VERSION 5.7 ;
BUSBITCHARS "[]" ;
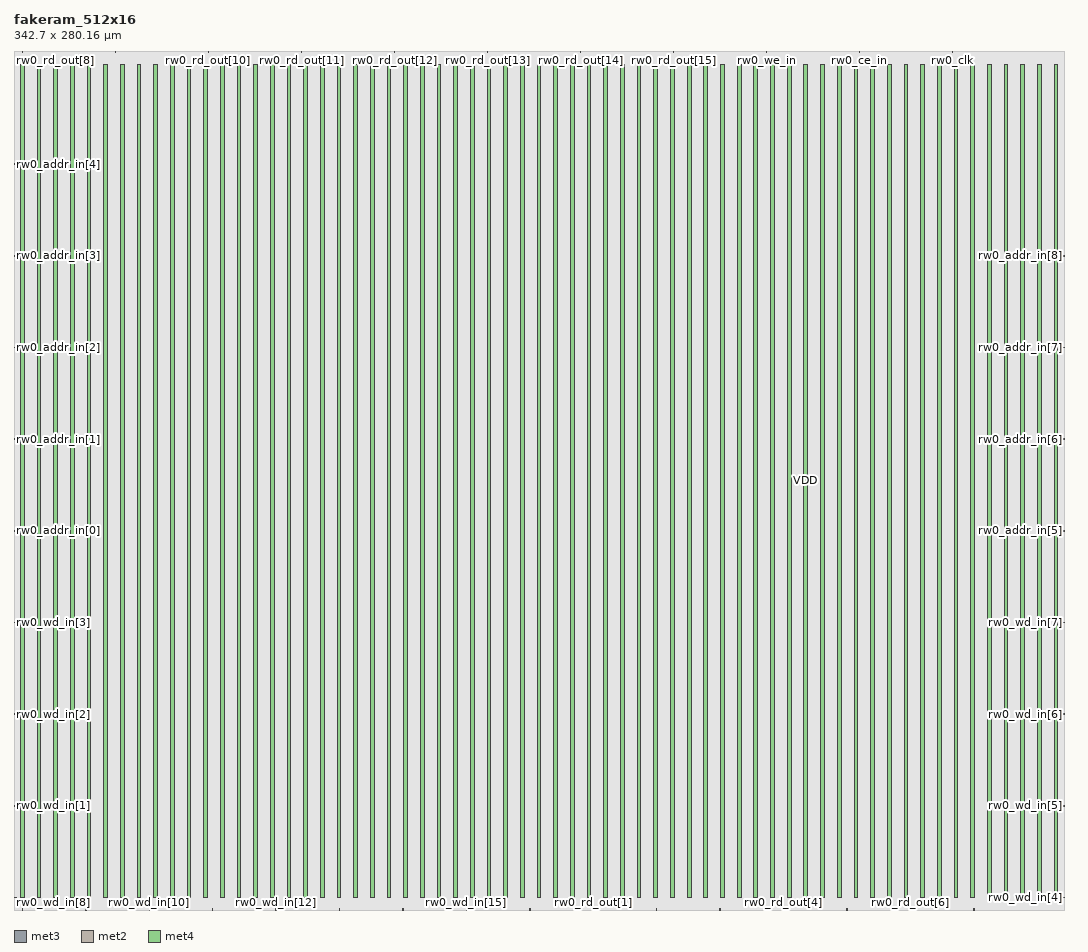
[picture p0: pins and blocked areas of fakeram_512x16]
MACRO fakeram_512x16
  FOREIGN fakeram_512x16 0 0 ;
  SYMMETRY X Y R90 ;
  SIZE 342.700 BY 280.160 ;
  CLASS BLOCK ;
  PIN rw0_wd_in[0]
    DIRECTION INPUT ;
    USE SIGNAL ;
    SHAPE ABUTMENT ;
    PORT
      LAYER met3 ;
      RECT 0.000 3.930 0.900 4.230 ;
    END
  END rw0_wd_in[0]
  PIN rw0_wd_in[1]
    DIRECTION INPUT ;
    USE SIGNAL ;
    SHAPE ABUTMENT ;
    PORT
      LAYER met3 ;
      RECT 0.000 33.850 0.900 34.150 ;
    END
  END rw0_wd_in[1]
  PIN rw0_wd_in[2]
    DIRECTION INPUT ;
    USE SIGNAL ;
    SHAPE ABUTMENT ;
    PORT
      LAYER met3 ;
      RECT 0.000 63.770 0.900 64.070 ;
    END
  END rw0_wd_in[2]
  PIN rw0_wd_in[3]
    DIRECTION INPUT ;
    USE SIGNAL ;
    SHAPE ABUTMENT ;
    PORT
      LAYER met3 ;
      RECT 0.000 93.690 0.900 93.990 ;
    END
  END rw0_wd_in[3]
  PIN rw0_wd_in[4]
    DIRECTION INPUT ;
    USE SIGNAL ;
    SHAPE ABUTMENT ;
    PORT
      LAYER met3 ;
      RECT 341.800 3.930 342.700 4.230 ;
    END
  END rw0_wd_in[4]
  PIN rw0_wd_in[5]
    DIRECTION INPUT ;
    USE SIGNAL ;
    SHAPE ABUTMENT ;
    PORT
      LAYER met3 ;
      RECT 341.800 33.850 342.700 34.150 ;
    END
  END rw0_wd_in[5]
  PIN rw0_wd_in[6]
    DIRECTION INPUT ;
    USE SIGNAL ;
    SHAPE ABUTMENT ;
    PORT
      LAYER met3 ;
      RECT 341.800 63.770 342.700 64.070 ;
    END
  END rw0_wd_in[6]
  PIN rw0_wd_in[7]
    DIRECTION INPUT ;
    USE SIGNAL ;
    SHAPE ABUTMENT ;
    PORT
      LAYER met3 ;
      RECT 341.800 93.690 342.700 93.990 ;
    END
  END rw0_wd_in[7]
  PIN rw0_wd_in[8]
    DIRECTION INPUT ;
    USE SIGNAL ;
    SHAPE ABUTMENT ;
    PORT
      LAYER met2 ;
      RECT 2.690 0.000 2.830 0.420 ;
    END
  END rw0_wd_in[8]
  PIN rw0_wd_in[9]
    DIRECTION INPUT ;
    USE SIGNAL ;
    SHAPE ABUTMENT ;
    PORT
      LAYER met2 ;
      RECT 23.390 0.000 23.530 0.420 ;
    END
  END rw0_wd_in[9]
  PIN rw0_wd_in[10]
    DIRECTION INPUT ;
    USE SIGNAL ;
    SHAPE ABUTMENT ;
    PORT
      LAYER met2 ;
      RECT 44.090 0.000 44.230 0.420 ;
    END
  END rw0_wd_in[10]
  PIN rw0_wd_in[11]
    DIRECTION INPUT ;
    USE SIGNAL ;
    SHAPE ABUTMENT ;
    PORT
      LAYER met2 ;
      RECT 64.790 0.000 64.930 0.420 ;
    END
  END rw0_wd_in[11]
  PIN rw0_wd_in[12]
    DIRECTION INPUT ;
    USE SIGNAL ;
    SHAPE ABUTMENT ;
    PORT
      LAYER met2 ;
      RECT 85.490 0.000 85.630 0.420 ;
    END
  END rw0_wd_in[12]
  PIN rw0_wd_in[13]
    DIRECTION INPUT ;
    USE SIGNAL ;
    SHAPE ABUTMENT ;
    PORT
      LAYER met2 ;
      RECT 106.190 0.000 106.330 0.420 ;
    END
  END rw0_wd_in[13]
  PIN rw0_wd_in[14]
    DIRECTION INPUT ;
    USE SIGNAL ;
    SHAPE ABUTMENT ;
    PORT
      LAYER met2 ;
      RECT 126.890 0.000 127.030 0.420 ;
    END
  END rw0_wd_in[14]
  PIN rw0_wd_in[15]
    DIRECTION INPUT ;
    USE SIGNAL ;
    SHAPE ABUTMENT ;
    PORT
      LAYER met2 ;
      RECT 147.590 0.000 147.730 0.420 ;
    END
  END rw0_wd_in[15]
  PIN rw0_rd_out[0]
    DIRECTION OUTPUT ;
    USE SIGNAL ;
    SHAPE ABUTMENT ;
    PORT
      LAYER met2 ;
      RECT 168.290 0.000 168.430 0.420 ;
    END
  END rw0_rd_out[0]
  PIN rw0_rd_out[1]
    DIRECTION OUTPUT ;
    USE SIGNAL ;
    SHAPE ABUTMENT ;
    PORT
      LAYER met2 ;
      RECT 188.990 0.000 189.130 0.420 ;
    END
  END rw0_rd_out[1]
  PIN rw0_rd_out[2]
    DIRECTION OUTPUT ;
    USE SIGNAL ;
    SHAPE ABUTMENT ;
    PORT
      LAYER met2 ;
      RECT 209.690 0.000 209.830 0.420 ;
    END
  END rw0_rd_out[2]
  PIN rw0_rd_out[3]
    DIRECTION OUTPUT ;
    USE SIGNAL ;
    SHAPE ABUTMENT ;
    PORT
      LAYER met2 ;
      RECT 230.390 0.000 230.530 0.420 ;
    END
  END rw0_rd_out[3]
  PIN rw0_rd_out[4]
    DIRECTION OUTPUT ;
    USE SIGNAL ;
    SHAPE ABUTMENT ;
    PORT
      LAYER met2 ;
      RECT 251.090 0.000 251.230 0.420 ;
    END
  END rw0_rd_out[4]
  PIN rw0_rd_out[5]
    DIRECTION OUTPUT ;
    USE SIGNAL ;
    SHAPE ABUTMENT ;
    PORT
      LAYER met2 ;
      RECT 271.790 0.000 271.930 0.420 ;
    END
  END rw0_rd_out[5]
  PIN rw0_rd_out[6]
    DIRECTION OUTPUT ;
    USE SIGNAL ;
    SHAPE ABUTMENT ;
    PORT
      LAYER met2 ;
      RECT 292.490 0.000 292.630 0.420 ;
    END
  END rw0_rd_out[6]
  PIN rw0_rd_out[7]
    DIRECTION OUTPUT ;
    USE SIGNAL ;
    SHAPE ABUTMENT ;
    PORT
      LAYER met2 ;
      RECT 313.190 0.000 313.330 0.420 ;
    END
  END rw0_rd_out[7]
  PIN rw0_rd_out[8]
    DIRECTION OUTPUT ;
    USE SIGNAL ;
    SHAPE ABUTMENT ;
    PORT
      LAYER met2 ;
      RECT 2.690 279.740 2.830 280.160 ;
    END
  END rw0_rd_out[8]
  PIN rw0_rd_out[9]
    DIRECTION OUTPUT ;
    USE SIGNAL ;
    SHAPE ABUTMENT ;
    PORT
      LAYER met2 ;
      RECT 33.050 279.740 33.190 280.160 ;
    END
  END rw0_rd_out[9]
  PIN rw0_rd_out[10]
    DIRECTION OUTPUT ;
    USE SIGNAL ;
    SHAPE ABUTMENT ;
    PORT
      LAYER met2 ;
      RECT 63.410 279.740 63.550 280.160 ;
    END
  END rw0_rd_out[10]
  PIN rw0_rd_out[11]
    DIRECTION OUTPUT ;
    USE SIGNAL ;
    SHAPE ABUTMENT ;
    PORT
      LAYER met2 ;
      RECT 93.770 279.740 93.910 280.160 ;
    END
  END rw0_rd_out[11]
  PIN rw0_rd_out[12]
    DIRECTION OUTPUT ;
    USE SIGNAL ;
    SHAPE ABUTMENT ;
    PORT
      LAYER met2 ;
      RECT 124.130 279.740 124.270 280.160 ;
    END
  END rw0_rd_out[12]
  PIN rw0_rd_out[13]
    DIRECTION OUTPUT ;
    USE SIGNAL ;
    SHAPE ABUTMENT ;
    PORT
      LAYER met2 ;
      RECT 154.490 279.740 154.630 280.160 ;
    END
  END rw0_rd_out[13]
  PIN rw0_rd_out[14]
    DIRECTION OUTPUT ;
    USE SIGNAL ;
    SHAPE ABUTMENT ;
    PORT
      LAYER met2 ;
      RECT 184.850 279.740 184.990 280.160 ;
    END
  END rw0_rd_out[14]
  PIN rw0_rd_out[15]
    DIRECTION OUTPUT ;
    USE SIGNAL ;
    SHAPE ABUTMENT ;
    PORT
      LAYER met2 ;
      RECT 215.210 279.740 215.350 280.160 ;
    END
  END rw0_rd_out[15]
  PIN rw0_addr_in[0]
    DIRECTION INPUT ;
    USE SIGNAL ;
    SHAPE ABUTMENT ;
    PORT
      LAYER met3 ;
      RECT 0.000 123.610 0.900 123.910 ;
    END
  END rw0_addr_in[0]
  PIN rw0_addr_in[1]
    DIRECTION INPUT ;
    USE SIGNAL ;
    SHAPE ABUTMENT ;
    PORT
      LAYER met3 ;
      RECT 0.000 153.530 0.900 153.830 ;
    END
  END rw0_addr_in[1]
  PIN rw0_addr_in[2]
    DIRECTION INPUT ;
    USE SIGNAL ;
    SHAPE ABUTMENT ;
    PORT
      LAYER met3 ;
      RECT 0.000 183.450 0.900 183.750 ;
    END
  END rw0_addr_in[2]
  PIN rw0_addr_in[3]
    DIRECTION INPUT ;
    USE SIGNAL ;
    SHAPE ABUTMENT ;
    PORT
      LAYER met3 ;
      RECT 0.000 213.370 0.900 213.670 ;
    END
  END rw0_addr_in[3]
  PIN rw0_addr_in[4]
    DIRECTION INPUT ;
    USE SIGNAL ;
    SHAPE ABUTMENT ;
    PORT
      LAYER met3 ;
      RECT 0.000 243.290 0.900 243.590 ;
    END
  END rw0_addr_in[4]
  PIN rw0_addr_in[5]
    DIRECTION INPUT ;
    USE SIGNAL ;
    SHAPE ABUTMENT ;
    PORT
      LAYER met3 ;
      RECT 341.800 123.610 342.700 123.910 ;
    END
  END rw0_addr_in[5]
  PIN rw0_addr_in[6]
    DIRECTION INPUT ;
    USE SIGNAL ;
    SHAPE ABUTMENT ;
    PORT
      LAYER met3 ;
      RECT 341.800 153.530 342.700 153.830 ;
    END
  END rw0_addr_in[6]
  PIN rw0_addr_in[7]
    DIRECTION INPUT ;
    USE SIGNAL ;
    SHAPE ABUTMENT ;
    PORT
      LAYER met3 ;
      RECT 341.800 183.450 342.700 183.750 ;
    END
  END rw0_addr_in[7]
  PIN rw0_addr_in[8]
    DIRECTION INPUT ;
    USE SIGNAL ;
    SHAPE ABUTMENT ;
    PORT
      LAYER met3 ;
      RECT 341.800 213.370 342.700 213.670 ;
    END
  END rw0_addr_in[8]
  PIN rw0_we_in
    DIRECTION INPUT ;
    USE SIGNAL ;
    SHAPE ABUTMENT ;
    PORT
      LAYER met2 ;
      RECT 245.570 279.740 245.710 280.160 ;
    END
  END rw0_we_in
  PIN rw0_ce_in
    DIRECTION INPUT ;
    USE SIGNAL ;
    SHAPE ABUTMENT ;
    PORT
      LAYER met2 ;
      RECT 275.930 279.740 276.070 280.160 ;
    END
  END rw0_ce_in
  PIN rw0_clk
    DIRECTION INPUT ;
    USE SIGNAL ;
    SHAPE ABUTMENT ;
    PORT
      LAYER met2 ;
      RECT 306.290 279.740 306.430 280.160 ;
    END
  END rw0_clk
  PIN VSS
    DIRECTION INOUT ;
    USE GROUND ;
    PORT
      LAYER met4 ;
      RECT 2.160 4.080 3.360 276.080 ;
      RECT 13.040 4.080 14.240 276.080 ;
      RECT 23.920 4.080 25.120 276.080 ;
      RECT 34.800 4.080 36.000 276.080 ;
      RECT 45.680 4.080 46.880 276.080 ;
      RECT 56.560 4.080 57.760 276.080 ;
      RECT 67.440 4.080 68.640 276.080 ;
      RECT 78.320 4.080 79.520 276.080 ;
      RECT 89.200 4.080 90.400 276.080 ;
      RECT 100.080 4.080 101.280 276.080 ;
      RECT 110.960 4.080 112.160 276.080 ;
      RECT 121.840 4.080 123.040 276.080 ;
      RECT 132.720 4.080 133.920 276.080 ;
      RECT 143.600 4.080 144.800 276.080 ;
      RECT 154.480 4.080 155.680 276.080 ;
      RECT 165.360 4.080 166.560 276.080 ;
      RECT 176.240 4.080 177.440 276.080 ;
      RECT 187.120 4.080 188.320 276.080 ;
      RECT 198.000 4.080 199.200 276.080 ;
      RECT 208.880 4.080 210.080 276.080 ;
      RECT 219.760 4.080 220.960 276.080 ;
      RECT 230.640 4.080 231.840 276.080 ;
      RECT 241.520 4.080 242.720 276.080 ;
      RECT 252.400 4.080 253.600 276.080 ;
      RECT 263.280 4.080 264.480 276.080 ;
      RECT 274.160 4.080 275.360 276.080 ;
      RECT 285.040 4.080 286.240 276.080 ;
      RECT 295.920 4.080 297.120 276.080 ;
      RECT 306.800 4.080 308.000 276.080 ;
      RECT 317.680 4.080 318.880 276.080 ;
      RECT 328.560 4.080 329.760 276.080 ;
      RECT 339.440 4.080 340.640 276.080 ;
    END
  END VSS
  PIN VDD
    DIRECTION INOUT ;
    USE POWER ;
    PORT
      LAYER met4 ;
      RECT 7.600 4.080 8.800 276.080 ;
      RECT 18.480 4.080 19.680 276.080 ;
      RECT 29.360 4.080 30.560 276.080 ;
      RECT 40.240 4.080 41.440 276.080 ;
      RECT 51.120 4.080 52.320 276.080 ;
      RECT 62.000 4.080 63.200 276.080 ;
      RECT 72.880 4.080 74.080 276.080 ;
      RECT 83.760 4.080 84.960 276.080 ;
      RECT 94.640 4.080 95.840 276.080 ;
      RECT 105.520 4.080 106.720 276.080 ;
      RECT 116.400 4.080 117.600 276.080 ;
      RECT 127.280 4.080 128.480 276.080 ;
      RECT 138.160 4.080 139.360 276.080 ;
      RECT 149.040 4.080 150.240 276.080 ;
      RECT 159.920 4.080 161.120 276.080 ;
      RECT 170.800 4.080 172.000 276.080 ;
      RECT 181.680 4.080 182.880 276.080 ;
      RECT 192.560 4.080 193.760 276.080 ;
      RECT 203.440 4.080 204.640 276.080 ;
      RECT 214.320 4.080 215.520 276.080 ;
      RECT 225.200 4.080 226.400 276.080 ;
      RECT 236.080 4.080 237.280 276.080 ;
      RECT 246.960 4.080 248.160 276.080 ;
      RECT 257.840 4.080 259.040 276.080 ;
      RECT 268.720 4.080 269.920 276.080 ;
      RECT 279.600 4.080 280.800 276.080 ;
      RECT 290.480 4.080 291.680 276.080 ;
      RECT 301.360 4.080 302.560 276.080 ;
      RECT 312.240 4.080 313.440 276.080 ;
      RECT 323.120 4.080 324.320 276.080 ;
      RECT 334.000 4.080 335.200 276.080 ;
    END
  END VDD
  OBS
    LAYER met1 ;
    RECT 0 0 342.700 280.160 ;
    LAYER met2 ;
    RECT 0 0 342.700 280.160 ;
    LAYER met3 ;
    RECT 0 0 342.700 280.160 ;
    LAYER met4 ;
    RECT 0 0 342.700 280.160 ;
  END
END fakeram_512x16

END LIBRARY
